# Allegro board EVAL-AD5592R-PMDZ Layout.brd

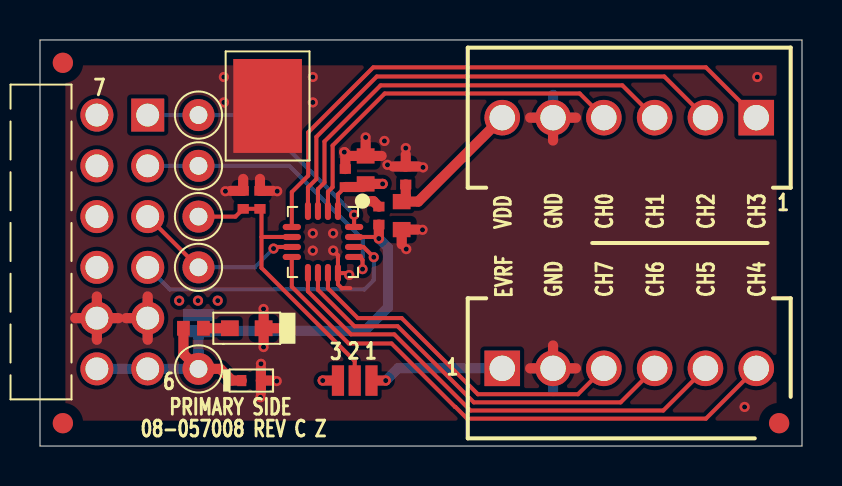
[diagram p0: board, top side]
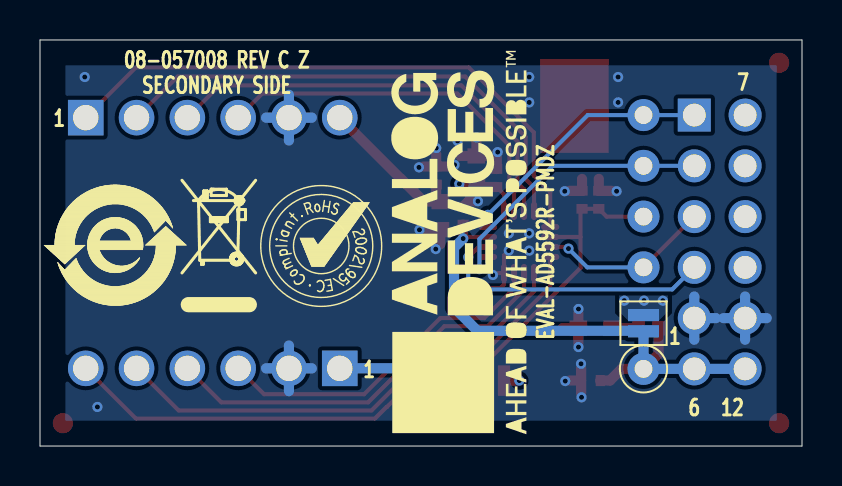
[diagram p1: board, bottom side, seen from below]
Outline 38.1 x 20.32 mm; copper layers: TOP, L2_GND, L3_PWR, BOTTOM. Coordinates in mm from the lower left corner of the outline.
Outline path: 0,20.32 0,0 38.1,0 38.1,20.32 0,20.32

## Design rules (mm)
constraint set DEFAULT: min track width 0.203

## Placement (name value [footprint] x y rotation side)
C1  0.1UF  [C0402]  11 12.32 90 top
C2  1UF  [C0402]  10.16 12.32 90 top
C3  0.1UF  [C0402]  16.94 11.53 90 top
C4  10UF  [C0603H47]  16.28 13.82 90 top
C5  0.1UF  [C0402]  15.27 13.41 90 top
C6  10UF  [C0603H47]  18.08 11.53 270 top
C7  0.1UF  [C0402]  18.29 13.54 90 top
D1  ESD9L5.0ST5G  [SOD923]  10.57 3.28 0 top
DS1  SML-D12P8WT86  [LED0603_A]  10.34 5.89 180 top
GND  5016  [CNKEY5016TP]  11.38 17.02 270 top
JP1  3PIN_SOLDER_JUMPER  [JPRSLD03]  15.74 3.28 180 top
MISO  TP_VIA  [TPC63D35]  7.92 8.94 0 top
MOSI  TP_VIA  [TPC63D35]  7.92 14.02 0 top
NOREF  -  []  20.12 36.29 0 top
NOREF#2  -  []  0 20.32 0 top
NOREF#3  -  []  0 0 0 top
NOREF#4  -  []  0 0 0 top
NOREF#5  -  []  81.22 56.03 0 top
NOREF#6  -  []  -66.5 -123.14 0 top
NOREF#7  -  [unnamed#2]  1.14 19.18 0 top
NOREF#8  -  [unnamed#2]  36.96 1.14 90 top
NOREF#9  -  []  0 20.32 0 top
NOREF#10  -  []  2.84 3.86 0 top
NOREF#11  -  []  96.19 -55.7 0 top
NOREF#12  -  []  38.1 20.32 180 top
NOREF#13  -  []  0 20.32 270 top
NOREF#14  -  []  38.1 0 90 top
NOREF#15  -  []  38.1 0 90 top
NOREF#16  -  []  -66.62 -123.14 0 top
NOREF#17  -  []  0 0 0 top
NOREF#18  -  []  21.01 185.47 270 top
NOREF#19  -  []  38.1 0 0 top
NOREF#20  -  []  33.32 259.89 0 top
NOREF#21  -  []  49.58 143.69 0 top
NOREF#22  -  [unnamed#2]  1.14 1.14 90 top
NOREF#23  -  []  2.84 3.86 0 top
NOREF#24  -  []  16.81 10.21 90 bottom
NOREF#25  -  []  49.78 2.49 180 bottom
P1  TSW-106-25-F-D-RA  [CNHDRRA2X6H240]  5.38 16.56 270 top
P2  OSTVN06A150  [CNOSTVN06A1X0]  23.11 3.89 0 top
P3  OSTVN06A150  [CNOSTVN06A1X0]  35.81 16.43 180 top
P8  -  [JPSLD02]  7.92 6.15 90 bottom
R1  1K  [R0402]  7.67 5.89 0 top
SS  TP_VIA  [TPC63D35]  7.92 16.56 0 top
U1  AD5592RBCPZ-1-RL7  [QFN16_3X3_A]  14.15 10.21 180 top
VLOGIC  TP_VIA  [TPC63D35]  7.92 3.86 0 top
VREF  TP_VIA  [TPC63D35]  7.92 11.48 0 top

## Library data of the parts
C1 C3 C5 C7 = CAP: User Part Number: UPN; Tolerance: 10; alternate symbols: C0402L; part number: CAP_SM-0.1UF,16V,10,E027519,C0402; tolerance: 10
C2 = CAP: User Part Number: UPN; Tolerance: 10; alternate symbols: C0402L; part number: CAP_SM-1UF,10V,10,E033897,C0402; tolerance: 10
C4 C6 = CAP: User Part Number: UPN; Tolerance: 10; alternate symbols: C0603L; part number: CAP_SM-10UF,10V,10,E034975,C0603H47; tolerance: 10
D1 = DIOZNR: User Part Number: UPN; Tolerance: N/A; alternate symbols: (); part number: DIOZNR_SM-ESD9L5.0ST5G,5V,N/A,E012879,SOD923; tolerance: N/A
DS1 = DIOLED: User Part Number: UPN; Tolerance: N/A; alternate symbols: (); part number: DIOLED_SM-SML-D12P8WT86,2.2V,N/A,E027457,LED0603_A; tolerance: N/A
GND = CNTP1P: Tolerance: N/A; User Part Number: UPN; alternate symbols: (); part number: CNTP1P_SM-5016,E005890,CNKEY5016TP; tolerance: N/A
JP1 = NC3P_JMPR: Tolerance: N/A; User Part Number: UPN; alternate symbols: (); part number: NC3P_JMPR_SM-3PIN_SOLDER_JUMPER,E005606,JPRSLD03; tolerance: N/A
MISO MOSI SS VLOGIC VREF = NCTESTPAD: Tolerance: N/A; User Part Number: UPN; alternate symbols: (); part number: NCTESTPAD_TH-TP_VIA,E012149,TPC63D35; tolerance: N/A
P1 = CN12P: User Part Number: UPN; Tolerance: N/A; alternate symbols: (); part number: CN12P_TH-TSW-106-25-F-D-RA,E018495,CNHDRRA2X6H240; tolerance: N/A
P2 P3 = CN6P: User Part Number: UPN; Tolerance: N/A; alternate symbols: (); part number: CN6P_TH-OSTVN06A150,E039593,CNOSTVN06A1X0; tolerance: N/A
P8 = NC2P: User Part Number: UPN; Tolerance: N/A; alternate symbols: (); part number: NC2P_SM-JPSLD02,E006230,JPSLD02; tolerance: N/A
R1 = RES: User Part Number: UPN; Tolerance: 5; alternate symbols: (R0402L); part number: RES_SM-1K,E020936,1/16W,5,R0402; tolerance: 5
U1 = AD5592R_1: User Part Number: UPN; Tolerance: N/A; alternate symbols: (); part number: AD5592R_1_SM-AD5592RBCPZ-1-RL7,E028324,QFN16_3X3_A; tolerance: N/A

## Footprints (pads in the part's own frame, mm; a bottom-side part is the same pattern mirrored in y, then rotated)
C0402
  rect 0.483x0.559 smd: 1(-0.45,0) 2(0.45,0)
C0603H47
  rect 0.762x0.889 smd: 1(-0.7,0) 2(0.7,0)
CNHDRRA2X6H240
  rect 1.651x1.651 hole 1.143: 1(0,0)
  round 1.651 hole 1.143: 2(2.54,0) 3(5.08,0) 4(7.62,0) 5(10.16,0) 6(12.7,0) 7(0,-2.54) 8(2.54,-2.54) 9(5.08,-2.54) 10(7.62,-2.54) 11(10.16,-2.54) 12(12.7,-2.54)
CNKEY5016TP
  rect 4.699x3.429 smd: 1(0,0)
CNOSTVN06A1X0
  rect 1.778x1.778 hole 1.27: 1(0,0)
  round 1.778 hole 1.27: 2(2.54,0) 3(5.08,0) 4(7.62,0) 5(10.16,0) 6(12.7,0)
JPRSLD03
  rect 0.61x1.524 smd: 1(-0.838,0) 2(0,0) 3(0.838,0)
JPSLD02
  rect 0.61x1.549 smd: 1(-0.406,0) 2(0.406,0)
LED0603_A
  rect 0.889x0.787 smd: A(0.845,0) C(-0.845,0)
QFN16_3X3_A
  oval 0.305x0.914 smd: 1(-0.75,-1.557) 2(-0.25,-1.557) 3(0.25,-1.557) 4(0.75,-1.557) 9(0.75,1.557) 10(0.25,1.557) 11(-0.25,1.557) 12(-0.75,1.557)
  oval 0.914x0.305 smd: 5(1.557,-0.75) 6(1.557,-0.25) 7(1.557,0.25) 8(1.557,0.75) 13(-1.557,0.75) 14(-1.557,0.25) 15(-1.557,-0.25) 16(-1.557,-0.75)
R0402
  rect 0.635x0.737 smd: 1(-0.5,0) 2(0.5,0)
SOD923
  rect 0.457x0.559 smd: A(0.479,0) C(-0.479,0)
TPC63D35
  round 1.6 hole 0.889: 1(0,0)
unnamed#2
  round 1.016 smd: (0,0)

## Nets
GND: C1.2(N2) C2.2(N2) C3.2(N2) C4.2(N2) C5.2(N2) C6.2(N2) C7.2(N2) D1.A(P) DS1.C GND.1(N1) P1.5 P1.11 P2.2 P3.5 U1.12
VDD: C4.1 C5.1 C6.1 C7.1 JP1.3 P3.6(N6) P8.2(N2) U1.1
EXT_VREF: JP1.1 P2.1
I/O0: P3.4 U1.2
I/O1: P3.3 U1.3
I/O2: P3.2 U1.4
I/O3: P3.1 U1.5
I/O4: P2.6(N6) U1.8
I/O5: P2.5 U1.9
I/O6: P2.4 U1.10
I/O7: P2.3 U1.11
MISO: MISO.1(N1) P1.3 U1.7
MOSI: MOSI.1(N1) P1.2 U1.13
SCK: P1.4 U1.14
SS: P1.1 SS.1(N1) U1.16
UNNAMED_2_DIOLED_I112_P: DS1.A(P) R1.2(N2)
VLOGIC: C3.1 D1.C P1.6 P1.12 P8.1 R1.1 U1.15 VLOGIC.1(N1)
VREF: C1.1 C2.1 JP1.2(COM) U1.6(VREF) VREF.1(N1)

Pads without a net: P1 7 8 9 10

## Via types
v1: diameter 0.508, hole 0.254, TOP to BOTTOM, 38 vias

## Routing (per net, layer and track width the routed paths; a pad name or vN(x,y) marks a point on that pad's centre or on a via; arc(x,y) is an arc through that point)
GND: length 66.1
  TOP w0.203: v1(14.66,9.78) 14.9,9.55 U1.12 ; 15.52,7.9 15.09,7.9 14.9,8.09 U1.12 ; U1.12 15.36,8.65 v1(15.46,8.56)
  TOP w0.508: D1.A 11.04,3.91 ; D1.A 11.63,3.28 ; D1.A 11.04,2.64 ; 10.16,13.37 C2.2 9.52,12.77 ; v1(15.21,14.71) 15.27,14.66 C5.2 ; P1.11 2.84,7.48 ; P1.11 3.92,6.4 ; P1.11 2.84,5.32 ; P1.11 1.76,6.4 ; 15.48,14.52 C4.2 ; C4.2 16.28,15.25 ; C4.2 17.08,14.52 ; C3.2 16.67,12.25 v1(16.21,12.25) ; P2.2 25.65,5.03 ; P2.2 26.8,3.89 ; P2.2 24.51,3.89 ; 4.3,6.4 P1.5 ; P1.5 5.38,7.48 ; P1.5 5.38,5.32 ; 24.51,16.43 P3.5 ; P3.5 26.8,16.43 ; P3.5 25.65,15.29 ; 18.08,10.09 C6.2 18.89,10.83 ; DS1.C 11.98,5.89 ; DS1.C 11.18,5.14 ; DS1.C 11.18,6.64 ; 17.65,13.99 C7.2 ; C7.2 18.92,13.99 ; C7.2 18.29,14.59 ; 11,13.37 C1.2 11.63,12.77
  L2_GND w0.508: 5.38,5.32 P1.5 ; P1.5 4.3,6.4 ; P1.5 5.38,7.48 ; P1.5 6.46,6.4 ; P2.2 25.65,5.03 ; P2.2 24.51,3.89 ; P2.2 25.65,2.74 ; P2.2 26.8,3.89 ; 2.84,5.32 P1.11 ; P1.11 2.84,7.48 ; P1.11 1.76,6.4 ; P1.11 3.92,6.4 ; P3.5 26.8,16.43 ; P3.5 24.51,16.43 ; P3.5 25.65,17.58 ; P3.5 25.65,15.29
  BOTTOM w0.508: 4.3,6.4 P1.5 ; P1.5 5.38,7.48 ; P1.5 5.38,5.32 ; P3.5 26.8,16.43 ; P3.5 25.65,15.29 ; P3.5 25.65,17.58 ; P3.5 24.51,16.43 ; 2.84,5.32 P1.11 ; P1.11 3.92,6.4 ; P1.11 2.84,7.48 ; P1.11 1.76,6.4 ; 24.51,3.89 P2.2 ; P2.2 25.65,5.03 ; P2.2 26.8,3.89 ; P2.2 25.65,2.74
  vias: v1(9.19,18.47) v1(9.19,17.2) v1(9.27,12.75) v1(11.05,4.11) v1(11.02,2.44) v1(11.18,6.86) v1(11.18,4.95) v1(11.86,12.75) v1(11.84,3.25) v1(13.64,18.47) v1(13.64,17.2) v1(13.64,10.64) v1(13.64,9.78) v1(14.66,10.64) v1(16.28,15.44) v1(17.22,15.27) v1(17.37,14.07) v1(18.29,14.91) v1(18.31,9.86) v1(19.15,13.94) v1(19.13,10.82) v1(35.23,1.96) v1(35.86,18.47)
VDD: length 16.3
  TOP w0.203: C5.1 14.9,12.59 U1.1
  TOP w0.508: P3.6 18.91,12.23 C6.1 18.29,12.43 C7.1 ; JP1.3 v1(14.14,3.28) ; C5.1 16.12,12.96 C4.1 v1(17.13,13.12)
  L3_PWR w0.508: 21.97,16.43 P3.6 ; P3.6 23.11,17.58 ; P3.6 24.26,16.43 ; P3.6 23.11,15.29
  vias: v1(6.96,7.27) v1(7.9,7.28) v1(8.89,7.28)
EXT_VREF: length 6.8
  TOP w0.508: JP1.1 v1(17.29,3.28)
  BOTTOM w0.508: P2.1 17.9,3.89 v1(17.29,3.28)
I/O0: length 18.5
  TOP w0.203: U1.2 14.4,12.72 14.63,12.95 14.63,15.04 17.23,17.64 26.98,17.64 P3.4
I/O1: length 21.9
  TOP w0.203: U1.3 13.9,12.86 14.22,13.18 14.22,15.24 17.03,18.05 29.12,18.05 P3.3
I/O2: length 25.4
  TOP w0.203: U1.4 13.4,12.94 13.82,13.36 13.82,15.47 16.84,18.49 31.21,18.49 P3.2
I/O3: length 29.9
  TOP w0.203: U1.5 12.59,12.71 13.41,13.53 13.41,15.7 16.66,18.95 33.3,18.95 P3.1
I/O4: length 28.5
  TOP w0.203: U1.8 12.59,7.97 15.43,5.13 17.58,5.13 20.75,1.96 20.77,1.96 21.35,1.37 33.3,1.37 P2.6
I/O5: length 24.1
  TOP w0.203: U1.9 13.4,7.74 15.55,5.59 17.71,5.59 21.52,1.78 31.16,1.78 P2.5
I/O6: length 20.7
  TOP w0.203: U1.10 13.9,7.82 15.72,5.99 17.88,5.99 21.69,2.18 29.03,2.18 P2.4
I/O7: length 17.3
  TOP w0.203: U1.11 14.4,7.89 15.89,6.4 18.09,6.4 21.9,2.59 26.9,2.59 P2.3
MISO: length 8.7
  TOP w0.203: P1.3 MISO.1 ; v1(11.68,9.88) 11.76,9.96 U1.7
  BOTTOM w0.203: MISO.1 10.74,8.94 v1(11.68,9.88)
MOSI: length 14.7
  TOP w0.203: U1.13 15.98,9.46 16.13,9.31 v1(16.13,8.85)
  BOTTOM w0.203: P1.2 MOSI.1 12.46,14.02 16.13,10.36 v1(16.13,8.85)
SCK: length 14.3
  TOP w0.203: U1.14 16.18,9.96 v1(16.69,9.45)
  BOTTOM w0.203: P1.4 6.49,7.84 16.22,7.84 16.69,8.31 v1(16.69,9.45)
SS: length 13
  TOP w0.203: v1(15.71,11.57) U1.16
  BOTTOM w0.203: P1.1 SS.1 10.71,16.56 v1(15.71,11.57)
UNNAMED_2_DIOLED_I112_P: length 1.3
  TOP w0.508: R1.2 DS1.A
VLOGIC: length 27.3
  TOP w0.203: v1(16.94,10.38) 16.86,10.46 U1.15
  TOP w0.508: D1.C 9.6,3.28 9.02,3.86 VLOGIC.1 7.17,4.61 R1.1 ; C3.1 v1(16.94,10.38)
  BOTTOM w0.508: P1.12 P1.6 VLOGIC.1 P8.1 7.95,5.77 16.23,5.77 17.4,6.93 17.4,9.93 v1(16.94,10.38)
VREF: length 15.3
  TOP w0.203: 11.07,10.46 11.07,8.92 15.74,4.25 JP1.2 ; 11.07,10.46 11.07,11.79 C1.1 C2.1 9.77,11.48 VREF.1 ; 11.07,10.46 U1.6

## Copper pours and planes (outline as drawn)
GND on TOP: 1.27,1.27 36.83,1.27 36.83,19.05 1.27,19.05 ; 1 cut-out
GND on BOTTOM, L2_GND: 1.27,1.27 36.83,1.27 36.83,19.05 1.27,19.05
VDD on BOTTOM: 6.71,6.73 6.71,7.54 9.14,7.54 9.14,6.73 8.69,6.27 7.16,6.27
VDD on L3_PWR: 1.27,1.27 36.83,1.27 36.83,19.05 1.27,19.05

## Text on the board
Ref Des/Silkscreen Bottom: EVAL-AD5592R-PMDZ
User.Comments: 5.    ASSEMBLY VENDOR MUST SOLDER SHORT ON DEFAULT POSISTION PIN 1 & 2 | OF THE COMPONENTS JP1.
Ref Des/Silkscreen Top: VDD | EVRF | GND | CH0 | CH7 | CH1 | CH6 | CH2 | CH5 | CH3 | CH4
PAGE_OUTLINE: 05MAR19 | B | C | AS PER ECR-089174 | AS PER ECR-090068 | 28JUN19 | 06SEP19 | J.PENAFLOR | EVAL-AD5592R-PMDZ
DIMENSION: " " | (REF) | DIA MAX
User.11: 3 | 2 | 1
User.12: 1 | OF THE COMPONENT P8. | 6.    ASSEMBLY VENDOR MUST SOLDER SHORT ON DEFAULT POSISTION PIN 1 & 2
User.17: L2 GND | 08-      -07
User.18: L3 PWR | 08-      -08
User.45: FIGURE | SIZE | 10.0 | 35.0 | 45.0 | 50.0 | PLATED | DRILL CHART: TOP to BOTTOM | ALL UNITS ARE IN MILS | QTY | 38 | 5 | 12 | TOLERANCE/NOTES
